One B-rep face of a CAD part: STEP entity #1524.
In plain terms, the planar face has unit normal (1, 0, 0).
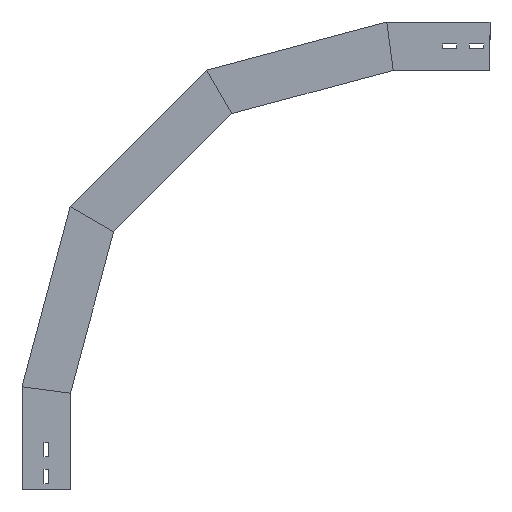
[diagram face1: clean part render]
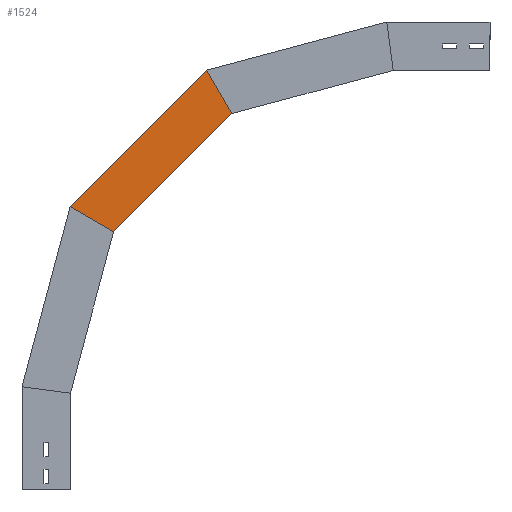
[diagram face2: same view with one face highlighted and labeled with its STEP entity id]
Its self-contained STEP definition (entity closure, numbers rounded to 3 decimals):
#148 = CARTESIAN_POINT ( 'NONE',  ( 0., -67.034, 400.175 ) ) ;
#206 = DIRECTION ( 'NONE',  ( 0., -0.707, 0.707 ) ) ;
#279 = ORIENTED_EDGE ( 'NONE', *, *, #998, .F. ) ;
#403 = ORIENTED_EDGE ( 'NONE', *, *, #508, .F. ) ;
#506 = VECTOR ( 'NONE', #1387, 1000. ) ;
#508 = EDGE_CURVE ( 'NONE', #776, #1265, #1108, .T. ) ;
#530 = VECTOR ( 'NONE', #550, 1000. ) ;
#535 = FACE_OUTER_BOUND ( 'NONE', #1204, .T. ) ;
#537 = LINE ( 'NONE', #971, #530 ) ;
#550 = DIRECTION ( 'NONE',  ( 0., -0.5, -0.866 ) ) ;
#662 = CARTESIAN_POINT ( 'NONE',  ( 0., 1.701, 437.506 ) ) ;
#725 = AXIS2_PLACEMENT_3D ( 'NONE', #1429, #1411, #1584 ) ;
#776 = VERTEX_POINT ( 'NONE', #148 ) ;
#806 = LINE ( 'NONE', #662, #506 ) ;
#892 = VERTEX_POINT ( 'NONE', #1029 ) ;
#902 = CARTESIAN_POINT ( 'NONE',  ( 0., -250.175, 583.315 ) ) ;
#971 = CARTESIAN_POINT ( 'NONE',  ( 0., -286.565, 520.285 ) ) ;
#998 = EDGE_CURVE ( 'NONE', #1450, #776, #1508, .T. ) ;
#1029 = CARTESIAN_POINT ( 'NONE',  ( 0., -211.352, 650.559 ) ) ;
#1077 = DIRECTION ( 'NONE',  ( 0., -0.866, -0.5 ) ) ;
#1091 = EDGE_CURVE ( 'NONE', #892, #1265, #537, .T. ) ;
#1107 = CARTESIAN_POINT ( 'NONE',  ( 0., -127.544, 365.239 ) ) ;
#1108 = LINE ( 'NONE', #1394, #1332 ) ;
#1188 = ORIENTED_EDGE ( 'NONE', *, *, #1445, .T. ) ;
#1204 = EDGE_LOOP ( 'NONE', ( #1188, #1642, #403, #279 ) ) ;
#1244 = CARTESIAN_POINT ( 'NONE',  ( 0., 0.209, 438.998 ) ) ;
#1265 = VERTEX_POINT ( 'NONE', #902 ) ;
#1329 = VECTOR ( 'NONE', #1077, 1000. ) ;
#1332 = VECTOR ( 'NONE', #206, 1000. ) ;
#1387 = DIRECTION ( 'NONE',  ( 0., -0.707, 0.707 ) ) ;
#1394 = CARTESIAN_POINT ( 'NONE',  ( 0., -51.332, 384.473 ) ) ;
#1411 = DIRECTION ( 'NONE',  ( 1., 0., 0. ) ) ;
#1429 = CARTESIAN_POINT ( 'NONE',  ( 0., -51.332, 384.473 ) ) ;
#1445 = EDGE_CURVE ( 'NONE', #1450, #892, #806, .T. ) ;
#1450 = VERTEX_POINT ( 'NONE', #1244 ) ;
#1508 = LINE ( 'NONE', #1107, #1329 ) ;
#1524 = ADVANCED_FACE ( 'NONE', ( #535 ), #1695, .T. ) ;
#1584 = DIRECTION ( 'NONE',  ( 0., 0., -1. ) ) ;
#1642 = ORIENTED_EDGE ( 'NONE', *, *, #1091, .T. ) ;
#1695 = PLANE ( 'NONE',  #725 ) ;
